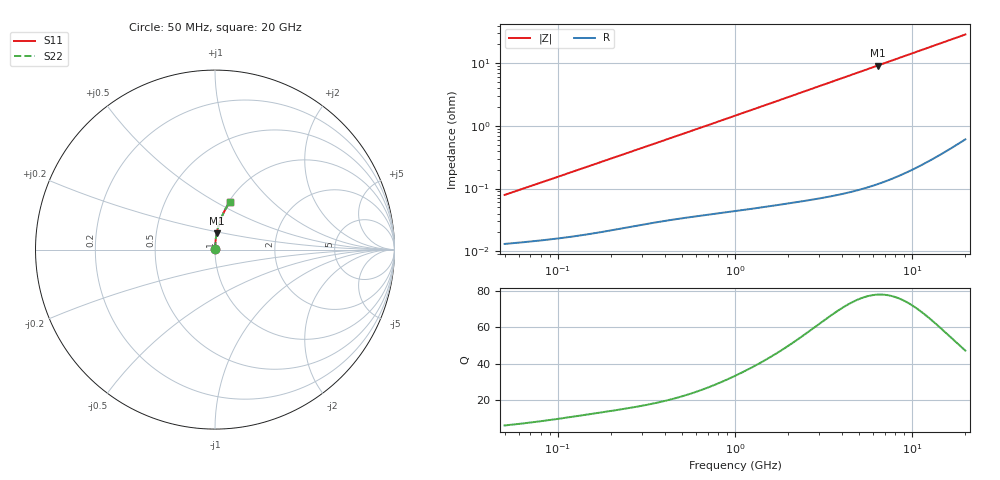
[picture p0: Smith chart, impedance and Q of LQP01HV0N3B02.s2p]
!Murata Part Number: LQP01HV0N3B02
!These Parameters are Measured in Series Mode Connection
!  o--[Z]--o
!Port1  Port2
!  o-------o
!Freq. Start=50[MHz] Stop=20[GHz], 401[Steps]
# Hz S RI R 50
!Freq.(Hz) S11(Real) S11(Imag) S21(Real) S21(Imag) S12(Real) S12(Imag) S22(Real) S22(Imag)
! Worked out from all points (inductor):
!   401 points, 50 MHz to 20 GHz, reference 50 ohm
!   read as one part in series: L = 247 pH near 51.52 MHz
!   highest Q = 78 at 6.407 GHz (marker M1), where L = 229 pH
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5e7  0.000131 0.000782  0.9999 -0.000782  0.9999 -0.000782  0.000131 0.000782
5.152053e7  0.000132 0.000805  0.9999 -0.000805  0.9999 -0.000805  0.000132 0.000805
5.470171e7  0.000135 0.000853  0.9999 -0.000853  0.9999 -0.000853  0.000135 0.000853
1.364002e8  0.000185 0.00208  0.9998 -0.00208  0.9998 -0.00208  0.000185 0.00208
3.721004e8  0.000325 0.00551  0.9997 -0.00551  0.9997 -0.00551  0.000325 0.00551
6.380365e8  0.000456 0.00933  0.9995 -0.00933  0.9995 -0.00933  0.000456 0.00933
1e9  0.000648 0.0145  0.9994 -0.0145  0.9994 -0.0145  0.000648 0.0145
1.714689e9  0.00116 0.0247  0.9988 -0.0247  0.9988 -0.0247  0.00116 0.0247
2.728004e9  0.0022 0.0392  0.9978 -0.0392  0.9978 -0.0392  0.0022 0.0392
3.466789e9  0.00323 0.0497  0.9968 -0.0497  0.9968 -0.0497  0.00323 0.0497
4.275624e9  0.00461 0.0612  0.9954 -0.0612  0.9954 -0.0612  0.00461 0.0612
5.273168e9  0.00669 0.0752  0.9933 -0.0752  0.9933 -0.0752  0.00669 0.0752
6.406762e9  0.00956 0.0911  0.9904 -0.0911  0.9904 -0.0911  0.00956 0.0911
7.442007e9  0.0126 0.1054  0.9874 -0.1054  0.9874 -0.1054  0.0126 0.1054
8.644534e9  0.0168 0.1219  0.9832 -0.1219  0.9832 -0.1219  0.0168 0.1219
9.892087e9  0.0217 0.1388  0.9783 -0.1388  0.9783 -0.1388  0.0217 0.1388
1.131968e10  0.028 0.1578  0.972 -0.1578  0.972 -0.1578  0.028 0.1578
1.295331e10  0.0362 0.179  0.9638 -0.179  0.9638 -0.179  0.0362 0.179
1.597544e10  0.0537 0.2167  0.9463 -0.2167  0.9463 -0.2167  0.0537 0.2167
1.774144e10  0.0653 0.2376  0.9347 -0.2376  0.9347 -0.2376  0.0653 0.2376
1.940974e10  0.0771 0.2566  0.9229 -0.2566  0.9229 -0.2566  0.0771 0.2566
2e10  0.0815 0.2631  0.9185 -0.2631  0.9185 -0.2631  0.0815 0.2631
